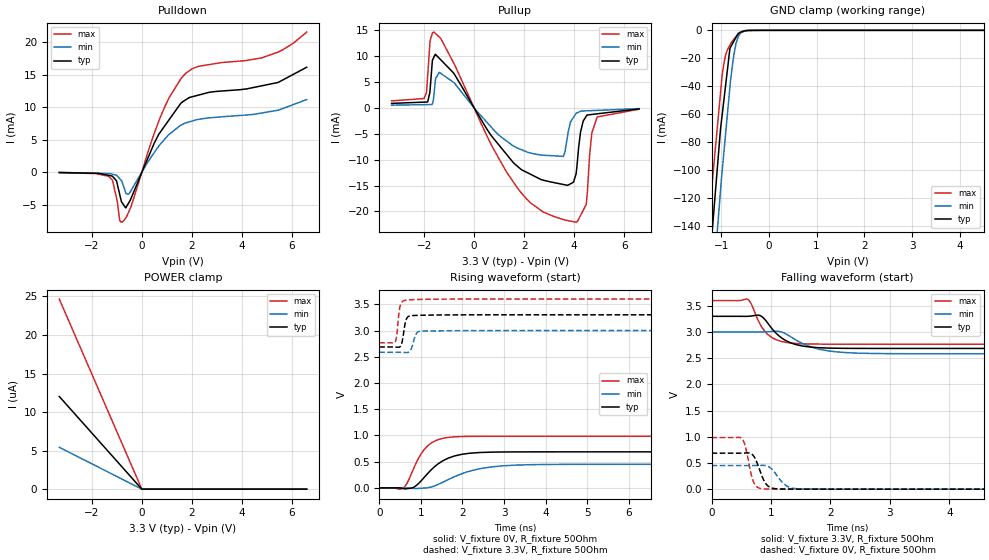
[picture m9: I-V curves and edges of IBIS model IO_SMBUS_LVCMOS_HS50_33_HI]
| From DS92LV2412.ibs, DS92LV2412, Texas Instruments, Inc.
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|   IO_SMBUS_LVCMOS_HS50_33_HI
[Model]   IO_SMBUS_LVCMOS_HS50_33_HI
Model_type   I/O
Polarity   Non-Inverting
Enable   Active-Low
Vinl = 0.8
Vinh = 2
Vmeas = 1.65
Vref = 1.65
Cref = 15pF
Rref = 50
|   typ   min   max
C_comp   0.7659pF   0.7659pF   0.7659pF
[Voltage Range]   3.3   3   3.6
[Temperature Range]   25   105   -40
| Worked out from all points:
|   slope of the pulldown table from 0 to 0.495 V, typ, clamps not added: 111 ohm
|   slope of the pullup table from 0 to 0.495 V, typ, clamps not added: 124 ohm
|   GND clamp passes 1 mA (typ) near -0.57 V on its own axis
|   falling waveform, V_fixture 3.3V, R_fixture 50Ohm: 20-80 % time 360ps typ, 506ps min, 262ps max; typ from 3.3 V to 2.69 V
|   rising waveform, V_fixture 0V, R_fixture 50Ohm: 20-80 % time 603ps typ, 913ps min, 415ps max; typ from 0 V to 0.687 V
|   rising waveform, V_fixture 3.3V, R_fixture 50Ohm: 20-80 % time 78.9ps typ, 97.2ps min, 69ps max; typ from 2.69 V to 3.3 V
|   falling waveform, V_fixture 0V, R_fixture 50Ohm: 20-80 % time 148ps typ, 198ps min, 114ps max; typ from 0.687 V to 0 V
[Pulldown]
|   Voltage   I(typ)   I(min)   I(max)
-3.3V     -70.73uA   -43.25uA   -91.37uA
-1.338V   -495uA     -228.7uA   -634.6uA
-1.176V   -649.9uA   -318.5uA   -1.218mA
-1.013V   -1.322mA   -498.7uA   -3.96mA
-891.4mV  -3.32mA    -976.4uA   -7.251mA
-792.4mV  -4.691mA   -1.488mA   -7.708mA
-643.7mV  -5.515mA   -3.161mA   -7.071mA
-530.9mV  -4.774mA   -3.389mA   -6.179mA
741.1mV   6.166mA    4.307mA    8.463mA
1.724V    11.05mA    7.523mA    15.09mA
4.794V    13.28mA    9.091mA    17.57mA
6.59V     16.13mA    11.16mA    21.54mA
[GND Clamp]
|   Voltage   I(typ)   I(min)   I(max)
-3.3V     -1.167A    -1.21A     -1.135A
-1.317V   -203mA     -250mA     -168.2mA
-1.176V   -139.3mA   -185.8mA   -104.9mA
-1.143V   -125.6mA   -170.9mA   -92.88mA
-1.013V   -70.86mA   -114.9mA   -45.06mA
-965.7mV  -56.87mA   -96.01mA   -28.91mA
-903.8mV  -38.74mA   -73.14mA   -17.62mA
-815.4mV  -12.86mA   -40.48mA   -10.59mA
-716.3mV  -6.717mA   -14.34mA   -5.636mA
-661.5mV  -3.317mA   -6.345mA   -3.702mA
-599.5mV  -1.363mA   -2.118mA   -2.066mA
6.59V     0A         0A         0A
[Pullup]
|   Voltage   I(typ)   I(min)   I(max)
-3.3V     885.6uA    535.6uA    1.373mA
-2.003V   1.128mA    639.7uA    1.823mA
-1.604V   9.868mA    2.779mA    14.66mA
-1.395V   9.602mA    6.883mA    13.71mA
1.29V     -8.935mA   -6.364mA   -12.35mA
2.667V    -13.82mA   -9.103mA   -19.78mA
3.561V    -14.78mA   -9.355mA   -21.55mA
4.068V    -12.83mA   -1.088mA   -22.07mA
4.479V    -1.607mA   -556.4uA   -18.65mA
4.703V    -1.249mA   -510.2uA   -4.812mA
4.915V    -1.129mA   -466.7uA   -1.743mA
6.59V     -180.2uA   -122.2uA   -236.2uA
[POWER Clamp]
|   Voltage   I(typ)   I(min)   I(max)
-3.3V     12.03uA    5.432uA    24.67uA
0V        0A         0A         0A
6.59V     0A         0A         0A
[Ramp]
R_load = 50
|   typ   min   max
dV/dt_r   0.412469/6.03251e-10   0.270193/9.12671e-10   0.590942/4.14549e-10
dV/dt_f   0.368091/3.5992e-10   0.248912/5.06415e-10   0.499879/2.61918e-10
[Falling Waveform]
V_fixture = 3.3V
V_fixture_min = 3V
V_fixture_max = 3.6V
R_fixture = 50Ohm
C_fixture = 0F
|   Time   V(typ)   V(min)   V(max)
0s        3.3V       3V         3.6V
607.6ps   3.3V       3V         3.624V
677.6ps   3.308V     3V         3.514V
818.8ps   3.314V     2.999V     3.145V
951.7ps   3.162V     3.006V     2.949V
1.121ns   2.94V      3.014V     2.84V
1.38ns    2.776V     2.876V     2.785V
1.824ns   2.7V       2.669V     2.769V
2.462ns   2.688V     2.597V     2.767V
10.05ns   2.687V     2.585V     2.767V
[Rising Waveform]
V_fixture = 0V
V_fixture_min = 0V
V_fixture_max = 0V
R_fixture = 50Ohm
C_fixture = 0F
|   Time   V(typ)   V(min)   V(max)
0s        3.216uV    4.065uV    1.972uV
589ps     -14.83mV   216.4uV    4.102mV
677.6ps   -13.35mV   -361.3uV   105mV
848.1ps   21.3mV     -11.91mV   407.2mV
1.081ns   200.2mV    -3.441mV   731.9mV
1.38ns    436.1mV    54.4mV     910.2mV
1.663ns   568.6mV    160.1mV    963.1mV
2.265ns   666.2mV    338.4mV    983mV
3.272ns   686.3mV    434.2mV    984.4mV
10.05ns   687.5mV    450.3mV    984.9mV
[Rising Waveform]
V_fixture = 3.3V
V_fixture_min = 3V
V_fixture_max = 3.6V
R_fixture = 50Ohm
C_fixture = 0F
|   Time   V(typ)   V(min)   V(max)
0s        2.687V     2.585V     2.767V
382.7ps   2.685V     2.585V     2.781V
417.3ps   2.683V     2.585V     2.889V
476.1ps   2.683V     2.585V     3.348V
508.3ps   2.699V     2.584V     3.484V
677.6ps   3.251V     2.583V     3.583V
762.9ps   3.283V     2.639V     3.587V
886.2ps   3.288V     2.935V     3.591V
1.021ns   3.292V     2.99V      3.594V
10.05ns   3.3V       3V         3.6V
[Falling Waveform]
|Gnd
V_fixture = 0V
V_fixture_min = 0V
V_fixture_max = 0V
R_fixture = 50Ohm
C_fixture = 0F
|   Time   V(typ)   V(min)   V(max)
0s        687.5mV    450.3mV    984.9mV
508.3ps   688.1mV    450.2mV    969.1mV
574.1ps   690.9mV    450.2mV    791.9mV
704.4ps   638.4mV    450.6mV    141.9mV
855.3ps   230.3mV    455mV      8.134mV
920.4ps   93.35mV    447.2mV    3.712mV
1.024ns   18.38mV    369.8mV    1.75mV
1.26ns    1.75mV     62.99mV    714.3uV
1.46ns    891.2uV    6.49mV     416.6uV
10.05ns   3.447uV    3.473uV    2.039uV
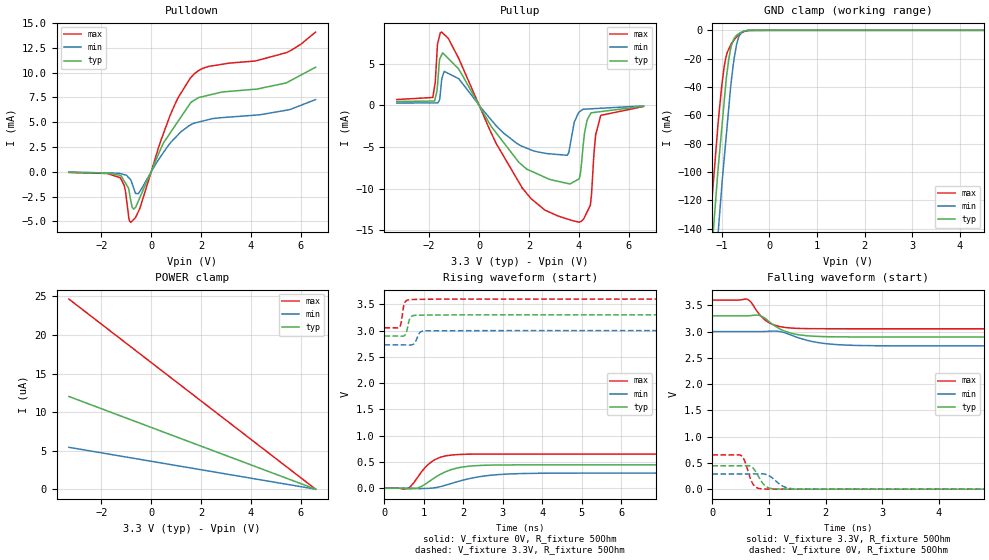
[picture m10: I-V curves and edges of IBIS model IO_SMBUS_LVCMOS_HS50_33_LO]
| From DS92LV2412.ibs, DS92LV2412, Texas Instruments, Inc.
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|   IO_SMBUS_LVCMOS_33_LO
[Model]   IO_SMBUS_LVCMOS_HS50_33_LO
Model_type   I/O
Polarity   Non-Inverting
Enable   Active-Low
Vinl = 0.8
Vinh = 2
Vmeas = 1.65
Vref = 1.65
Cref = 15pF
Rref = 50
|   typ   min   max
C_comp   0.7659pF   0.7659pF   0.7659pF
[Voltage Range]   3.3   3   3.6
[Temperature Range]   25   105   -40
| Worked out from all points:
|   slope of the pulldown table from 0 to 0.495 V, typ, clamps not added: 172 ohm
|   slope of the pullup table from 0 to 0.495 V, typ, clamps not added: 193 ohm
|   GND clamp passes 1 mA (typ) near -0.57 V on its own axis
|   falling waveform, V_fixture 3.3V, R_fixture 50Ohm: 20-80 % time 395ps typ, 558ps min, 285ps max; typ from 3.3 V to 2.9 V
|   rising waveform, V_fixture 0V, R_fixture 50Ohm: 20-80 % time 647ps typ, 970ps min, 464ps max; typ from 0 V to 0.445 V
|   rising waveform, V_fixture 3.3V, R_fixture 50Ohm: 20-80 % time 78.9ps typ, 100ps min, 68.6ps max; typ from 2.9 V to 3.3 V
|   falling waveform, V_fixture 0V, R_fixture 50Ohm: 20-80 % time 158ps typ, 207ps min, 124ps max; typ from 0.445 V to 0 V
[Pulldown]
|   Voltage   I(typ)   I(min)   I(max)
-3.3V     -45.57uA   -27.82uA   -59.19uA
-1.233V   -347.3uA   -179.6uA   -599.9uA
-1.08V    -932.2uA   -280.6uA   -1.38mA
-895.3mV  -1.819mA   -602.9uA   -4.672mA
-809.2mV  -3.009mA   -864.9uA   -5.074mA
-695.6mV  -3.752mA   -1.69mA    -4.785mA
-523mV    -2.998mA   -2.209mA   -4.049mA
752.8mV   3.885mA    2.865mA    5.654mA
1.714V    7.195mA    4.9mA      9.844mA
2.304V    7.724mA    5.271mA    10.62mA
5.422V    8.974mA    6.211mA    12.01mA
6.59V     10.54mA    7.281mA    14.08mA
[GND Clamp]
|   Voltage   I(typ)   I(min)   I(max)
-3.3V     -1.167A    -1.21A     -1.135A
-1.324V   -206.2mA   -254.1mA   -172mA
-1.233V   -164.8mA   -212.4mA   -129.9mA
-1.121V   -115.7mA   -161.1mA   -82.91mA
-1.08V    -97.73mA   -143.3mA   -65.53mA
-956.8mV  -52.17mA   -92.45mA   -26.8mA
-858.2mV  -21mA      -55.75mA   -13.41mA
-814.5mV  -12.87mA   -39.48mA   -10.3mA
-740.3mV  -5.609mA   -19.32mA   -6.615mA
-666.4mV  -2.945mA   -6.802mA   -3.802mA
-588.4mV  -1.219mA   -1.695mA   -1.801mA
6.59V     0A         0A         0A
[Pullup]
|   Voltage   I(typ)   I(min)   I(max)
-3.3V     446.5uA    269.8uA    684.9uA
-1.855V   507.2uA    276.5uA    934.3uA
-1.667V   2.415mA    277.4uA    7.333mA
-1.5V     6.05mA     3.039mA    8.769mA
2.181V    -8.017mA   -5.472mA   -11.43mA
3.535V    -9.36mA    -5.994mA   -13.63mA
4.009V    -8.822mA   -811.9uA   -14.01mA
4.226V    -3.312mA   -468.4uA   -13.41mA
4.461V    -1.046mA   -429.4uA   -11.98mA
4.671V    -840.1uA   -394.4uA   -3.557mA
4.878V    -761.8uA   -360.1uA   -1.21mA
6.59V     -112.2uA   -75.63uA   -148.2uA
[POWER Clamp]
|   Voltage   I(typ)   I(min)   I(max)
-3.3V     12.03uA    5.432uA    24.67uA
6.59V     0A         0A         0A
[Ramp]
R_load = 50
|   typ   min   max
dV/dt_r   0.267177/6.46611e-10   0.173456/9.69999e-10   0.390673/4.64183e-10
dV/dt_f   0.241629/3.95407e-10   0.163275/5.57558e-10   0.328055/2.85434e-10
[Falling Waveform]
V_fixture = 3.3V
V_fixture_min = 3V
V_fixture_max = 3.6V
R_fixture = 50Ohm
C_fixture = 0F
|   Time   V(typ)   V(min)   V(max)
0s        3.3V       3V         3.6V
606.8ps   3.3V       3V         3.618V
687.1ps   3.305V     3V         3.553V
822ps     3.311V     2.999V     3.339V
955ps     3.232V     3.004V     3.2V
1.181ns   3.057V     3.003V     3.098V
1.419ns   2.962V     2.922V     3.065V
1.882ns   2.907V     2.788V     3.054V
2.627ns   2.898V     2.734V     3.053V
10.05ns   2.897V     2.728V     3.053V
[Rising Waveform]
V_fixture = 0V
V_fixture_min = 0V
V_fixture_max = 0V
R_fixture = 50Ohm
C_fixture = 0F
|   Time   V(typ)   V(min)   V(max)
0s        2.706uV    3.446uV    1.71uV
606.8ps   -10.77mV   242.9uV    3.7mV
892.6ps   19.03mV    -8.8mV     262.9mV
1.179ns   152mV      685.4uV    495.6mV
1.419ns   266mV      31.67mV    590mV
1.716ns   358.9mV    95.39mV    633.5mV
2.018ns   409.1mV    159.3mV    645.8mV
2.627ns   438.9mV    242.6mV    650.6mV
3.526ns   444.9mV    280.9mV    650.8mV
10.05ns   445.3mV    289.1mV    651.1mV
[Rising Waveform]
V_fixture = 3.3V
V_fixture_min = 3V
V_fixture_max = 3.6V
R_fixture = 50Ohm
C_fixture = 0F
|   Time   V(typ)   V(min)   V(max)
0s        2.897V     2.728V     3.053V
387.2ps   2.897V     2.728V     3.067V
429.7ps   2.895V     2.728V     3.171V
504.6ps   2.903V     2.728V     3.513V
558.9ps   2.974V     2.727V     3.571V
658.7ps   3.249V     2.725V     3.589V
776.4ps   3.291V     2.774V     3.593V
895.3ps   3.293V     2.96V      3.594V
1.029ns   3.295V     2.994V     3.596V
10.05ns   3.3V       3V         3.6V
[Falling Waveform]
|Gnd
V_fixture = 0V
V_fixture_min = 0V
V_fixture_max = 0V
R_fixture = 50Ohm
C_fixture = 0F
|   Time   V(typ)   V(min)   V(max)
0s        445.3mV    289.1mV    651.1mV
504.6ps   445.5mV    289.1mV    642mV
568.5ps   447mV      289mV      544.6mV
721ps     398.2mV    289.4mV    88.07mV
784.8ps   300.7mV    290.2mV    26.84mV
905.1ps   94.03mV    289.1mV    4.235mV
1.018ns   17.54mV    245.5mV    1.697mV
1.254ns   1.612mV    51.04mV    713.1uV
1.496ns   709.8uV    3.813mV    360.5uV
10.05ns   2.653uV    2.534uV    1.959uV
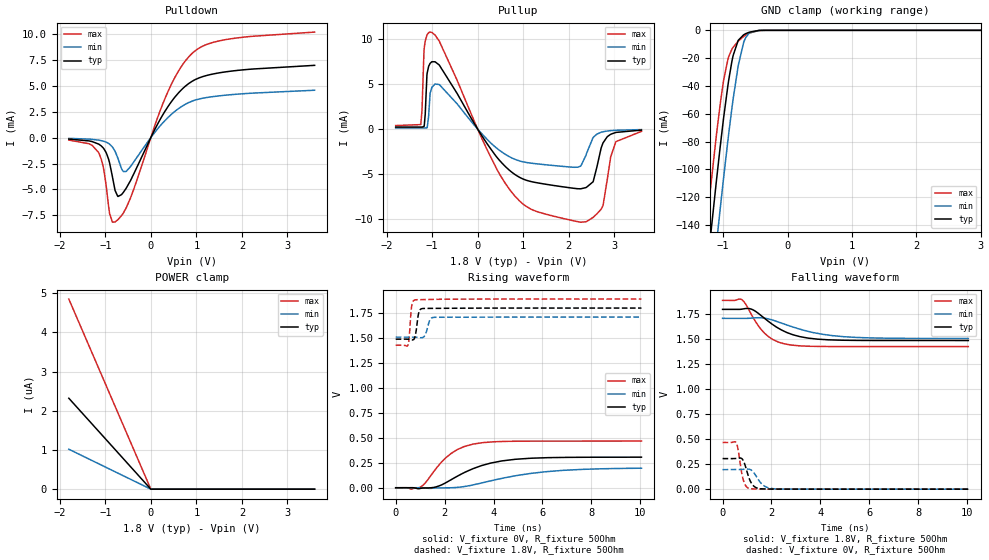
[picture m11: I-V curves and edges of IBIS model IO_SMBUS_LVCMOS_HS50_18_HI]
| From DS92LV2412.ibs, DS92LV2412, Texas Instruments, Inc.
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|   IO_SMBUS_LVCMOS_18_HI
[Model]   IO_SMBUS_LVCMOS_HS50_18_HI
Model_type   I/O
Polarity   Non-Inverting
Enable   Active-Low
Vinl = 0.63
Vinh = 1.17
Vmeas = 0.9
Vref = 0.9
Rref = 50
|   typ   min   max
C_comp   0.7659pF   0.7659pF   0.7659pF
[Voltage Range]   1.8   1.71   1.89
[Temperature Range]   25   105   -40
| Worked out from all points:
|   slope of the pulldown table from 0 to 0.27 V, typ, clamps not added: 120 ohm
|   slope of the pullup table from 0 to 0.27 V, typ, clamps not added: 130 ohm
|   GND clamp passes 1 mA (typ) near -0.55 V on its own axis
|   falling waveform, V_fixture 1.8V, R_fixture 50Ohm: 20-80 % time 1.25ns typ, 1.81ns min, 850ps max; typ from 1.8 V to 1.49 V
|   rising waveform, V_fixture 0V, R_fixture 50Ohm: 20-80 % time 1.73ns typ, 2.63ns min, 1.11ns max; typ from 0 V to 0.306 V
|   rising waveform, V_fixture 1.8V, R_fixture 50Ohm: 20-80 % time 107ps typ, 144ps min, 84.5ps max; typ from 1.49 V to 1.8 V
|   falling waveform, V_fixture 0V, R_fixture 50Ohm: 20-80 % time 263ps typ, 358ps min, 197ps max; typ from 0.306 V to 0 V
[Pulldown]
|   Voltage   I(typ)   I(min)   I(max)
-1.8V     -141.1uA   -72.17uA   -232.6uA
-1.147V   -619.8uA   -241uA     -1.432mA
-1.028V   -1.094mA   -361uA     -3.221mA
-903.6mV  -2.461mA   -635.9uA   -7.34mA
-784.8mV  -5.09mA    -1.311mA   -8.127mA
-720mV    -5.673mA   -2.024mA   -7.903mA
-541.8mV  -4.888mA   -3.264mA   -6.781mA
306mV     2.511mA    1.625mA    3.722mA
608.4mV   4.319mA    2.8mA      6.426mA
910.8mV   5.443mA    3.526mA    8.141mA
1.651V    6.347mA    4.096mA    9.453mA
3.595V    6.969mA    4.569mA    10.17mA
[GND Clamp]
|   Voltage   I(typ)   I(min)   I(max)
-1.8V     -432.2mA   -478.5mA   -397.7mA
-1.255V   -174.4mA   -221.2mA   -139.5mA
-1.19V    -145.3mA   -191.7mA   -110.9mA
-1.103V   -107.6mA   -153.3mA   -74.75mA
-1.044V   -82.96mA   -127.5mA   -52.43mA
-990mV    -61.92mA   -104.8mA   -35.27mA
-925.2mV  -39.37mA   -78.79mA   -20.71mA
-865.8mV  -22.74mA   -56.64mA   -13.72mA
-763.2mV  -7.086mA   -24.77mA   -7.683mA
-655.2mV  -2.529mA   -5.716mA   -3.512mA
-428.4mV  -69.59uA   -66.07uA   -127.6uA
3.595V    0A         0A         0A
[Pullup]
|   Voltage   I(typ)   I(min)   I(max)
-1.8V     230.7uA    134.2uA    399.2uA
-1.249V   228.9uA    133.1uA    502.6uA
-1.174V   375.6uA    133uA      8.992mA
-1.114V   6.016mA    138.2uA    10.45mA
-1.044V   7.315mA    3.987mA    10.79mA
457.2mV   -3.341mA   -2.275mA   -4.798mA
1.165V    -5.82mA    -3.776mA   -8.879mA
2.25V     -6.632mA   -4.133mA   -10.33mA
2.531V    -5.859mA   -949.6uA   -9.818mA
2.752V    -1.521mA   -290.1uA   -8.467mA
3.033V    -364.7uA   -126.7uA   -1.388mA
3.595V    -109.4uA   -52.56uA   -248uA
[POWER Clamp]
|   Voltage   I(typ)   I(min)   I(max)
-1.8V     2.321uA    1.019uA    4.851uA
0V        0A         0A         0A
3.595V    0A         0A         0A
[Ramp]
R_load = 50
|   typ   min   max
dV/dt_r   0.183701/1.72625e-09   0.117381/2.62978e-09   0.280452/1.11148e-09
dV/dt_f   0.187083/1.24683e-09   0.120864/1.81303e-09   0.277497/8.5047e-10
[Falling Waveform]
V_fixture = 1.8V
V_fixture_min = 1.71V
V_fixture_max = 1.89V
R_fixture = 50Ohm
C_fixture = 0F
|   Time   V(typ)   V(min)   V(max)
0s        1.8V       1.71V      1.89V
806.4ps   1.803V     1.71V      1.894V
940.3ps   1.808V     1.71V      1.854V
1.214ns   1.799V     1.713V     1.733V
1.713ns   1.711V     1.711V     1.562V
2.049ns   1.648V     1.693V     1.499V
2.513ns   1.582V     1.654V     1.456V
3.509ns   1.512V     1.579V     1.431V
4.958ns   1.491V     1.526V     1.428V
10.05ns   1.488V     1.509V     1.428V
[Rising Waveform]
V_fixture = 0V
V_fixture_min = 0V
V_fixture_max = 0V
R_fixture = 50Ohm
C_fixture = 0F
|   Time   V(typ)   V(min)   V(max)
0s        1.763uV    3.015uV    1.181uV
642.8ps   163.2uV    142.9uV    -14.28mV
1.043ns   -4.818mV   29.52uV    11.26mV
1.647ns   8.326mV    -1.66mV    191mV
2.049ns   50.27mV    -854.1uV   299.8mV
2.513ns   114.4mV    3.494mV    381.3mV
3.162ns   191mV      28.23mV    437mV
4.899ns   285.2mV    120mV      465.7mV
6.823ns   303.5mV    173.9mV    467.3mV
10.05ns   306.2mV    195.6mV    467.4mV
[Rising Waveform]
V_fixture = 1.8V
V_fixture_min = 1.71V
V_fixture_max = 1.89V
R_fixture = 50Ohm
C_fixture = 0F
|   Time   V(typ)   V(min)   V(max)
0s        1.488V     1.509V     1.427V
488.6ps   1.488V     1.509V     1.422V
558.9ps   1.486V     1.509V     1.525V
653.9ps   1.482V     1.509V     1.82V
806.4ps   1.529V     1.507V     1.882V
938.8ps   1.75V      1.505V     1.884V
1.099ns   1.795V     1.504V     1.884V
1.408ns   1.797V     1.686V     1.886V
1.55ns    1.797V     1.706V     1.887V
10.05ns   1.8V       1.71V      1.89V
[Falling Waveform]
|Gnd
V_fixture = 0V
V_fixture_min = 0V
V_fixture_max = 0V
R_fixture = 50Ohm
C_fixture = 0F
|   Time   V(typ)   V(min)   V(max)
0s        306.2mV    195.6mV    467.4mV
558.9ps   307.6mV    196.5mV    464.5mV
622.9ps   309.2mV    196.6mV    412.2mV
777.4ps   307.7mV    197.5mV    170.8mV
866.7ps   275.9mV    198.6mV    77.3mV
1.11ns    94.62mV    198.5mV    5.875mV
1.374ns   14.5mV     130.3mV    1.719mV
1.664ns   2.488mV    38.55mV    917.7uV
2.033ns   927.6uV    5.655mV    435.6uV
10.05ns   1.65uV     2.927uV    1.048uV
